VERSION 5.7 ;
  NOWIREEXTENSIONATPIN ON ;
  DIVIDERCHAR "/" ;
  BUSBITCHARS "[]" ;
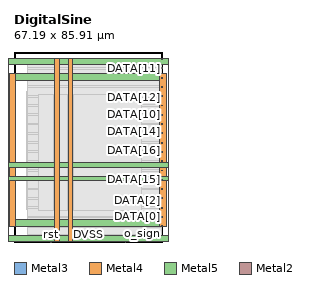
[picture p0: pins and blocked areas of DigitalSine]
MACRO DigitalSine
  CLASS BLOCK ;
  FOREIGN DigitalSine ;
  ORIGIN 0.000 0.000 ;
  SIZE 67.190 BY 85.910 ;
  PIN DATA[0]
    DIRECTION OUTPUT ;
    USE SIGNAL ;
    ANTENNADIFFAREA 0.708600 ;
    PORT
      LAYER Metal3 ;
        RECT 66.790 11.140 67.190 11.540 ;
    END
  END DATA[0]
  PIN DATA[10]
    DIRECTION OUTPUT ;
    USE SIGNAL ;
    ANTENNADIFFAREA 0.708600 ;
    PORT
      LAYER Metal3 ;
        RECT 66.790 57.340 67.190 57.740 ;
    END
  END DATA[10]
  PIN DATA[11]
    DIRECTION OUTPUT ;
    USE SIGNAL ;
    ANTENNADIFFAREA 0.708600 ;
    PORT
      LAYER Metal3 ;
        RECT 66.790 78.340 67.190 78.740 ;
    END
  END DATA[11]
  PIN DATA[12]
    DIRECTION OUTPUT ;
    USE SIGNAL ;
    ANTENNADIFFAREA 0.708600 ;
    PORT
      LAYER Metal3 ;
        RECT 66.790 61.540 67.190 61.940 ;
    END
  END DATA[12]
  PIN DATA[13]
    DIRECTION OUTPUT ;
    USE SIGNAL ;
    ANTENNADIFFAREA 0.708600 ;
    PORT
      LAYER Metal3 ;
        RECT 66.790 69.940 67.190 70.340 ;
    END
  END DATA[13]
  PIN DATA[14]
    DIRECTION OUTPUT ;
    USE SIGNAL ;
    ANTENNADIFFAREA 0.708600 ;
    PORT
      LAYER Metal3 ;
        RECT 66.790 53.140 67.190 53.540 ;
    END
  END DATA[14]
  PIN DATA[15]
    DIRECTION OUTPUT ;
    USE SIGNAL ;
    ANTENNADIFFAREA 0.708600 ;
    PORT
      LAYER Metal3 ;
        RECT 66.790 27.940 67.190 28.340 ;
    END
  END DATA[15]
  PIN DATA[16]
    DIRECTION OUTPUT ;
    USE SIGNAL ;
    ANTENNADIFFAREA 0.708600 ;
    PORT
      LAYER Metal3 ;
        RECT 66.790 44.740 67.190 45.140 ;
    END
  END DATA[16]
  PIN DATA[17]
    DIRECTION OUTPUT ;
    USE SIGNAL ;
    ANTENNADIFFAREA 0.708600 ;
    PORT
      LAYER Metal3 ;
        RECT 66.790 40.540 67.190 40.940 ;
    END
  END DATA[17]
  PIN DATA[1]
    DIRECTION OUTPUT ;
    USE SIGNAL ;
    ANTENNADIFFAREA 0.708600 ;
    PORT
      LAYER Metal3 ;
        RECT 66.790 19.540 67.190 19.940 ;
    END
  END DATA[1]
  PIN DATA[2]
    DIRECTION OUTPUT ;
    USE SIGNAL ;
    ANTENNADIFFAREA 0.708600 ;
    PORT
      LAYER Metal3 ;
        RECT 66.790 15.340 67.190 15.740 ;
    END
  END DATA[2]
  PIN DATA[3]
    DIRECTION OUTPUT ;
    USE SIGNAL ;
    ANTENNADIFFAREA 0.708600 ;
    PORT
      LAYER Metal3 ;
        RECT 66.790 36.340 67.190 36.740 ;
    END
  END DATA[3]
  PIN DATA[4]
    DIRECTION OUTPUT ;
    USE SIGNAL ;
    ANTENNADIFFAREA 0.708600 ;
    PORT
      LAYER Metal3 ;
        RECT 66.790 23.740 67.190 24.140 ;
    END
  END DATA[4]
  PIN DATA[5]
    DIRECTION OUTPUT ;
    USE SIGNAL ;
    ANTENNADIFFAREA 0.708600 ;
    PORT
      LAYER Metal3 ;
        RECT 66.790 48.940 67.190 49.340 ;
    END
  END DATA[5]
  PIN DATA[6]
    DIRECTION OUTPUT ;
    USE SIGNAL ;
    ANTENNADIFFAREA 0.708600 ;
    PORT
      LAYER Metal3 ;
        RECT 66.790 32.140 67.190 32.540 ;
    END
  END DATA[6]
  PIN DATA[7]
    DIRECTION OUTPUT ;
    USE SIGNAL ;
    ANTENNADIFFAREA 0.708600 ;
    PORT
      LAYER Metal3 ;
        RECT 66.790 74.140 67.190 74.540 ;
    END
  END DATA[7]
  PIN DATA[8]
    DIRECTION OUTPUT ;
    USE SIGNAL ;
    ANTENNADIFFAREA 0.708600 ;
    PORT
      LAYER Metal3 ;
        RECT 66.790 65.740 67.190 66.140 ;
    END
  END DATA[8]
  PIN DATA[9]
    DIRECTION OUTPUT ;
    USE SIGNAL ;
    ANTENNADIFFAREA 0.708600 ;
    PORT
      LAYER Metal3 ;
        RECT 66.790 82.540 67.190 82.940 ;
    END
  END DATA[9]
  PIN DVDD
    DIRECTION INOUT ;
    USE POWER ;
    PORT
      LAYER Metal4 ;
        RECT -2.240 7.120 0.760 76.040 ;
    END
    PORT
      LAYER Metal4 ;
        RECT 65.960 7.120 68.960 76.040 ;
    END
    PORT
      LAYER Metal5 ;
        RECT -2.240 7.120 68.960 10.120 ;
    END
    PORT
      LAYER Metal5 ;
        RECT -2.240 73.040 68.960 76.040 ;
    END
    PORT
      LAYER Metal4 ;
        RECT 18.260 0.120 20.460 83.040 ;
    END
    PORT
      LAYER Metal5 ;
        RECT -9.240 27.620 75.960 29.820 ;
    END
  END DVDD
  PIN DVSS
    DIRECTION INOUT ;
    USE GROUND ;
    PORT
      LAYER Metal4 ;
        RECT -9.240 0.120 -6.240 83.040 ;
    END
    PORT
      LAYER Metal4 ;
        RECT 72.960 0.120 75.960 83.040 ;
    END
    PORT
      LAYER Metal5 ;
        RECT -9.240 0.120 75.960 3.120 ;
    END
    PORT
      LAYER Metal5 ;
        RECT -9.240 80.040 75.960 83.040 ;
    END
    PORT
      LAYER Metal4 ;
        RECT 24.460 0.120 26.660 83.040 ;
    END
    PORT
      LAYER Metal5 ;
        RECT -9.240 33.820 75.960 36.020 ;
    END
  END DVSS
  PIN clk
    DIRECTION INPUT ;
    USE SIGNAL ;
    ANTENNAGATEAREA 1.450800 ;
    PORT
      LAYER Metal2 ;
        RECT 50.200 0.000 50.600 0.400 ;
    END
  END clk
  PIN o_sign
    DIRECTION OUTPUT ;
    USE SIGNAL ;
    ANTENNADIFFAREA 0.708600 ;
    PORT
      LAYER Metal3 ;
        RECT 66.790 6.940 67.190 7.340 ;
    END
  END o_sign
  PIN o_signB
    DIRECTION OUTPUT ;
    USE SIGNAL ;
    ANTENNADIFFAREA 0.708600 ;
    PORT
      LAYER Metal3 ;
        RECT 66.790 2.740 67.190 3.140 ;
    END
  END o_signB
  PIN rst
    DIRECTION INPUT ;
    USE SIGNAL ;
    ANTENNAGATEAREA 0.180700 ;
    PORT
      LAYER Metal2 ;
        RECT 16.600 0.000 17.000 0.400 ;
    END
  END rst
  OBS
      LAYER GatPoly ;
        RECT 5.760 14.970 60.960 68.190 ;
      LAYER Metal1 ;
        RECT 5.760 14.900 60.960 68.260 ;
      LAYER Metal2 ;
        RECT 6.135 0.610 64.905 82.885 ;
        RECT 6.135 0.100 16.390 0.610 ;
        RECT 17.210 0.100 49.990 0.610 ;
        RECT 50.810 0.100 64.905 0.610 ;
      LAYER Metal3 ;
        RECT 6.095 82.330 66.580 82.840 ;
        RECT 6.095 78.950 66.790 82.330 ;
        RECT 6.095 78.130 66.580 78.950 ;
        RECT 6.095 74.750 66.790 78.130 ;
        RECT 6.095 73.930 66.580 74.750 ;
        RECT 6.095 70.550 66.790 73.930 ;
        RECT 6.095 69.730 66.580 70.550 ;
        RECT 6.095 66.350 66.790 69.730 ;
        RECT 6.095 65.530 66.580 66.350 ;
        RECT 6.095 62.150 66.790 65.530 ;
        RECT 6.095 61.330 66.580 62.150 ;
        RECT 6.095 57.950 66.790 61.330 ;
        RECT 6.095 57.130 66.580 57.950 ;
        RECT 6.095 53.750 66.790 57.130 ;
        RECT 6.095 52.930 66.580 53.750 ;
        RECT 6.095 49.550 66.790 52.930 ;
        RECT 6.095 48.730 66.580 49.550 ;
        RECT 6.095 45.350 66.790 48.730 ;
        RECT 6.095 44.530 66.580 45.350 ;
        RECT 6.095 41.150 66.790 44.530 ;
        RECT 6.095 40.330 66.580 41.150 ;
        RECT 6.095 36.950 66.790 40.330 ;
        RECT 6.095 36.130 66.580 36.950 ;
        RECT 6.095 32.750 66.790 36.130 ;
        RECT 6.095 31.930 66.580 32.750 ;
        RECT 6.095 28.550 66.790 31.930 ;
        RECT 6.095 27.730 66.580 28.550 ;
        RECT 6.095 24.350 66.790 27.730 ;
        RECT 6.095 23.530 66.580 24.350 ;
        RECT 6.095 20.150 66.790 23.530 ;
        RECT 6.095 19.330 66.580 20.150 ;
        RECT 6.095 15.950 66.790 19.330 ;
        RECT 6.095 15.130 66.580 15.950 ;
        RECT 6.095 11.750 66.790 15.130 ;
        RECT 6.095 10.930 66.580 11.750 ;
        RECT 6.095 7.550 66.790 10.930 ;
        RECT 6.095 6.730 66.580 7.550 ;
        RECT 6.095 3.350 66.790 6.730 ;
        RECT 6.095 2.840 66.580 3.350 ;
      LAYER Metal4 ;
        RECT 10.940 14.135 18.050 66.505 ;
        RECT 20.670 14.135 24.250 66.505 ;
        RECT 26.870 14.135 57.700 66.505 ;
  END
END DigitalSine
END LIBRARY

